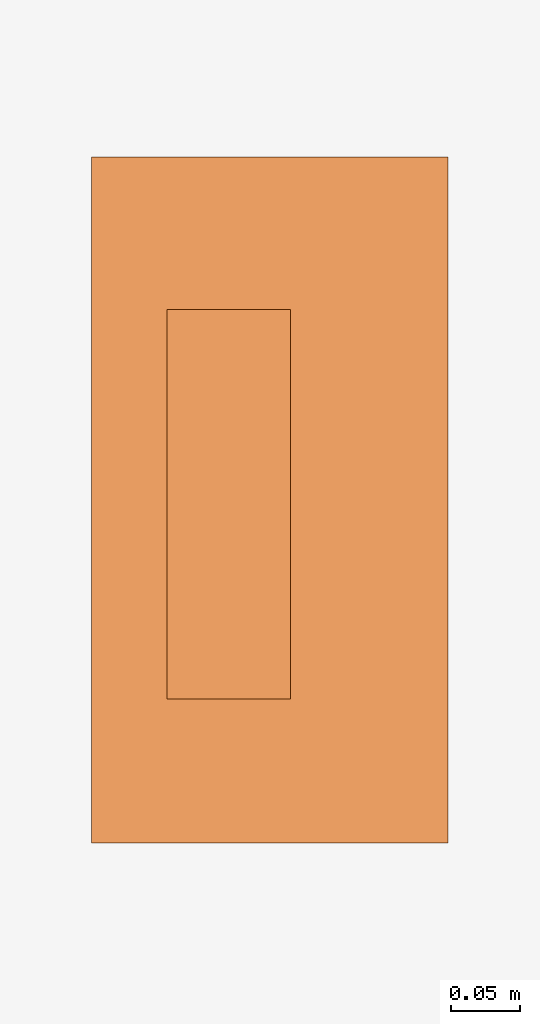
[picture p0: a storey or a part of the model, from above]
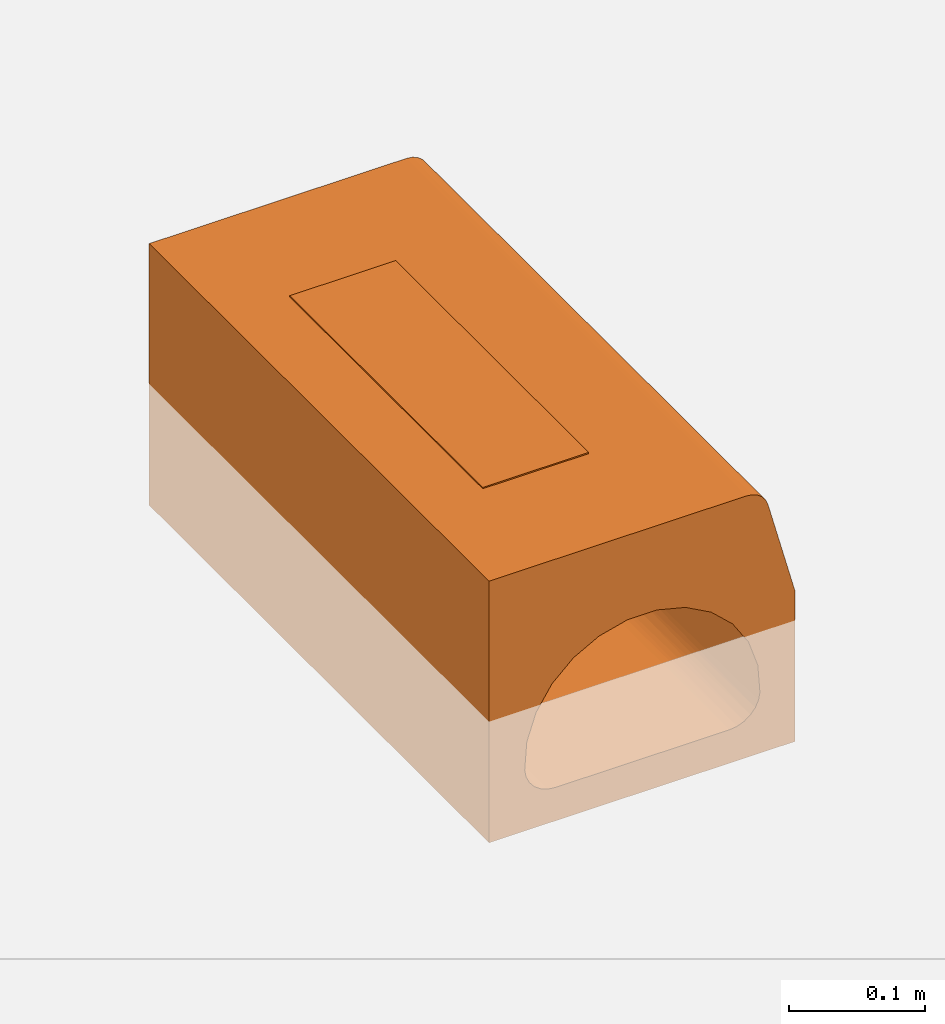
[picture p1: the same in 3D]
Properties of the parts of a building model (IFC2X3)

# File
Description: ViewDefinition [CoordinationView]
File name: T0130 - Access unit - 500mm LG - 235mm High.ifc
Time: 2013-09-04T09:02:06
Written by: Autodesk Revit 2013
Made in: 20120221_2030(x64)

# IfcProject, Project Number
LongName: Project Name; Phase: Project Status

# IfcSite, Default
RefLatitude: 42, 21, 30, 344238; RefLongitude: -71, -3, -35, -194702; RefElevation: 0 mm

# IfcBuilding
Pset_BuildingCommon - NumberOfStoreys: 1
Other - Project Number: Project Number; Project Address: ## Street City, State Zip; Project Issue Date: Issue Date; Client Name: Owner; Project Name: Project Name; Project Status: Project Status

# IfcBuildingStorey, Level 1
LongName: Level 1; Elevation: 0 mm
Constraints - Elevation Base: 0; Elevation: 0 mm
Graphics - Symbol at End 2 Default: yes; Line Pattern: Center; Color: 0; Line Weight: 1; Symbol: M_Level Head - Circle: M_Level Head - Circle; Symbol at End 1 Default: no
Dimensions - Computation Height: 0 mm
Identity Data - Building Story: yes; Name: Level 1; Structural: no

# IfcBuildingElementProxy: T0130 - Access unit - 500mm LG - 235mm High, Civil-Drainage-Channel-ACO-KerbDrain-KD200:T0130 - Access unit - 500mm LG - 235mm High:T0130 - Access unit - 500mm LG - 235mm High:308203
In: Level 1
Material: ACO Polymer Concrete., Iron, Cast
Dimensions - Volume: 19033186 mm3; Void Depth.: -110 mm; Void length: 500 mm
Phasing - Phase Created: New Construction
Constraints - Moves With Nearby Elements: no; Level: Level: Level 1
Pset_BuildingElementProxyCommon - Reference: T0130 - Access unit - 500mm LG - 235mm High
General - SerialNumber: 0.000000; TagNumber: 0.000000
Identity Data - Assembly Description: Rain Water Drainage; Manufacturer: ACO Technologies plc - ACO Water Management Division; Product Page URL: http://www.aco.co.uk/product_detail.php?id=3; Fax: +44 (0)1462 815895; Assembly Code: D2040; Model: ACO KerbDrain KD200; Model Description: Combined kerb and drainage system; Product Code: T0130; e-mail Technical: technical@aco.co.uk; OmniClass Title: Rainwater Removal; e-mail Sales: customersupport@aco.co.uk; URL: www.aco.co.uk; Price: POA - contact ACO; Address: ACO Business Park, Hitchin Road, Shefford, Bedfordshire, United Kingdom SG17 5TE; Telephone: +44 (0)1462 816666; Cost: 0; Product brochure: http://www.aco.co.uk/download.php?id=120; Installation guidelines: http://www.aco.co.uk/download.php?id=120; Type Comments: ACO KerbDrain KD200 half battered rodding access unit 235mm high 500mm long; OmniClass Number: 23.70.50.24; Maintenance guidelines: http://www.aco.co.uk/download.php?id=120
Other - Revision: 1; CreatedBy: www.aco.co.uk
Materials and Finishes - Channel Colour: Grey; Access Cover/Frame Finish: Water Based Paint Coating; End Cap Material: N/A; Access Cover/Frame Colour: Black; End Cap Colour: N/A; Channel Material: Vienite® Synthetic Resin Concrete; Access Cover/Frame Material: Ductile Iron
Construction - Access Cover: yes; Accessunit_220: no; Accessunit_235: yes; Channelunit_220: no; Blindunit_235: no; Blindunit_220: no; Channelunit_235: no; Closing end cap: no
Data - Drainage Slot Width: N/A; Installation - Concrete Grade: Refer to brochure; Load Class: A 15 - D 400 A 15 - D 400; Channel C.S.A: 0.02m²; Drainage Slot Intake area: N/A; Product Weight: 41.5 Kg; Concrete Surround Volume - Load Class A 15 - D 400 - Concrete Pavement: 0.20m³/m; Product Standard: BS EN 1433:2002, CE marked, Kitemarked; Product Dimensions: 500mm x 260mm x 235mm (LxWxH); Hydraulic Performance: http://www.aco.co.uk/download.php?id=120; Invert Depth: 205mm; ACO Hydraulic Design Software: http://www.acodesign.co.uk
Green Building Properties - End Cap Recyclable: N/A; End Cap Recycled Material Content: N/A; Channel Recycled Material Content: 20% minimum; Channel Recyclable: Fully recyclable; Access Cover/Frame Recyclable: Fully recyclable; Access Cover/Frame Recycled Material Content: Between 40% - 90%

# IfcOpeningElement: Recess
In: Level 1
Structural - Enable Analytical Model: no; Structural: no
Dimensions - Perimeter: 51360 mm; Area: 151470000 mm2; Volume: 60573700000 mm3; Thickness: 400 mm
Constraints - Room Bounding: yes; Level: Level: Level 1; Related to Mass: no; Height Offset From Level: 0 mm
Phasing - Phase Created: New Construction
Materials and Finishes - Structural Material: Plant
Construction - Default Thickness: 400 mm; Function: 0
Graphics - Coarse Scale Fill Color: 0
Analytical Properties - Roughness: 1; Absorptance: 0.1

# IfcSlab: Floor:Generic Floor - 400mm, Floor:Generic Floor - 400mm:193825
In: Level 1
PredefinedType: FLOOR; Material: Plant 400 mm
Structural - Enable Analytical Model: no; Structural: no
Dimensions - Perimeter: 51360 mm; Area: 151470000 mm2; Volume: 60573700000 mm3; Thickness: 400 mm
Constraints - Room Bounding: yes; Level: Level: Level 1; Related to Mass: no; Height Offset From Level: 0 mm
Phasing - Phase Created: New Construction
Pset_SlabCommon - Reference: Generic Floor - 400mm; IsExternal: no; LoadBearing: yes
Materials and Finishes - Structural Material: Plant
Construction - Default Thickness: 400 mm; Function: 0
Graphics - Coarse Scale Fill Color: 0
Analytical Properties - Roughness: 1; Absorptance: 0.1
